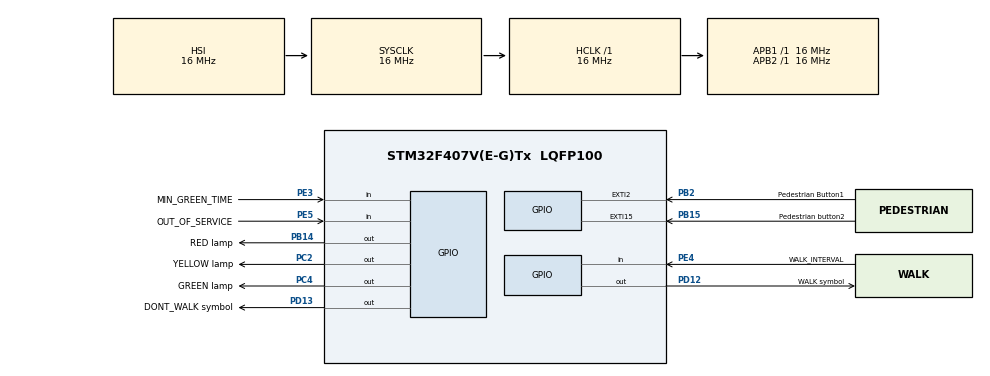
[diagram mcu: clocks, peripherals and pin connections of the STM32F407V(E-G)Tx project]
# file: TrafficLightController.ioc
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Mcu.Family=STM32F4
Mcu.Name=STM32F407V(E-G)Tx
Mcu.Package=LQFP100
NVIC.PriorityGroup=NVIC_PRIORITYGROUP_4
PA13.Mode=Serial_Wire
PA13.Signal=SYS_JTMS-SWDIO
PA14.Mode=Serial_Wire
PA14.Signal=SYS_JTCK-SWCLK
PB14.GPIO_Label=RED lamp
PB14.Signal=GPIO_Output
PB15.GPIO_Label=Pedestrian button2
PB15.GPIO_ModeDefaultEXTI=GPIO_MODE_IT_FALLING
PB15.Signal=GPXTI15
PB2.GPIO_Label=Pedestrian Button1
PB2.GPIO_ModeDefaultEXTI=GPIO_MODE_IT_FALLING
PB2.Signal=GPXTI2
PC2.GPIO_Label=YELLOW lamp
PC2.Signal=GPIO_Output
PC4.GPIO_Label=GREEN lamp
PC4.Signal=GPIO_Output
PD12.GPIO_Label=WALK symbol
PD12.Signal=GPIO_Output
PD13.GPIO_Label=DONT_WALK symbol
PD13.Signal=GPIO_Output
PE3.GPIO_Label=MIN_GREEN_TIME
PE3.Signal=GPIO_Input
PE4.GPIO_Label=WALK_INTERVAL
PE4.Signal=GPIO_Input
PE5.GPIO_Label=OUT_OF_SERVICE
PE5.Signal=GPIO_Input
ProjectManager.HeapSize=0x200
ProjectManager.StackSize=0x400
ProjectManager.TargetToolchain=MDK-ARM V5
RCC.AHBFreq_Value=16000000
RCC.APB1Freq_Value=16000000
RCC.APB2Freq_Value=16000000
RCC.CortexFreq_Value=16000000
RCC.HSE_VALUE=25000000
RCC.HSI_VALUE=16000000
RCC.LSE_VALUE=32768
RCC.SYSCLKFreq_VALUE=16000000
RCC.VCOOutputFreq_Value=192000000
board=custom

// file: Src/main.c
/* USER CODE BEGIN Header */
/**
  ******************************************************************************
  * @file           : main.c
  * @brief          : Main program body
  ******************************************************************************
  * @attention
  *
  * <h2><center>&copy; Copyright (c) 2019 STMicroelectronics.
  * All rights reserved.</center></h2>
  *
  * This software component is licensed by ST under BSD 3-Clause license,
  * the "License"; You may not use this file except in compliance with the
  * License. You may obtain a copy of the License at:
  *                        opensource.org/licenses/BSD-3-Clause
  *
  ******************************************************************************
  */
/* USER CODE END Header */

#include "main.h"

/* USER CODE BEGIN Includes */
#include <stdio.h>
#include "bsp.h"
#include "timer.h"
#include "ctrler.h"
/* USER CODE END Includes */

void SystemClock_Config(void);
static void MX_GPIO_Init(void);

/* USER CODE BEGIN 0 */
int fputc(int ch, FILE *f)
{
	return ITM_SendChar(ch);
}

Event_t Event_Detect()
{
	Event_t evt = NO_EVT ;
							if (Timeout_Status){
									evt = TIMEOUT ;
									Timeout_Status = 0 ;
							}

							if (Button_Status) {
									evt = BUTTON ;
									Button_Status = 0 ;
							}

							if (MODE_READ()) {
									evt = MODE_CHANGE ;
							}
	return evt ;
}
/* USER CODE END 0 */

int main(void)
{

  /* MCU Configuration--------------------------------------------------------*/

  /* Reset of all peripherals, Initializes the Flash interface and the Systick. */
  HAL_Init();

  /* Configure the system clock */
  SystemClock_Config();

  /* Initialize all configured peripherals */
  MX_GPIO_Init();

  /* Infinite loop */
  while (1)
  {

    /* USER CODE BEGIN 3 */

		Event_t evt = Event_Detect(); //detect event
		uint32_t timeout_value = Ctrler_Exec(evt) ; //Execute state machine, return timeout
		Timeout_Config(timeout_value) ; //set timeout value in timer
		MIN_GREEN_TIME = GREEN_TIME_READ() ? 600:1200 ;
		WALK_INTERVAL = WALK_READ() ? 100:200 ;
		Delay(1);
  }
  /* USER CODE END 3 */
}

void SystemClock_Config(void)
{
  RCC_OscInitTypeDef RCC_OscInitStruct = {0};
  RCC_ClkInitTypeDef RCC_ClkInitStruct = {0};

  /** Configure the main internal regulator output voltage
  */
  __HAL_RCC_PWR_CLK_ENABLE();
  __HAL_PWR_VOLTAGESCALING_CONFIG(PWR_REGULATOR_VOLTAGE_SCALE1);
  /** Initializes the CPU, AHB and APB busses clocks
  */
  RCC_OscInitStruct.OscillatorType = RCC_OSCILLATORTYPE_HSI;
  RCC_OscInitStruct.HSIState = RCC_HSI_ON;
  RCC_OscInitStruct.HSICalibrationValue = RCC_HSICALIBRATION_DEFAULT;
  RCC_OscInitStruct.PLL.PLLState = RCC_PLL_NONE;
  if (HAL_RCC_OscConfig(&RCC_OscInitStruct) != HAL_OK)
  {
    Error_Handler();
  }
  /** Initializes the CPU, AHB and APB busses clocks
  */
  RCC_ClkInitStruct.ClockType = RCC_CLOCKTYPE_HCLK|RCC_CLOCKTYPE_SYSCLK
                              |RCC_CLOCKTYPE_PCLK1|RCC_CLOCKTYPE_PCLK2;
  RCC_ClkInitStruct.SYSCLKSource = RCC_SYSCLKSOURCE_HSI;
  RCC_ClkInitStruct.AHBCLKDivider = RCC_SYSCLK_DIV1;
  RCC_ClkInitStruct.APB1CLKDivider = RCC_HCLK_DIV1;
  RCC_ClkInitStruct.APB2CLKDivider = RCC_HCLK_DIV1;

  if (HAL_RCC_ClockConfig(&RCC_ClkInitStruct, FLASH_LATENCY_0) != HAL_OK)
  {
    Error_Handler();
  }
}

static void MX_GPIO_Init(void)
{
  GPIO_InitTypeDef GPIO_InitStruct = {0};

  /* GPIO Ports Clock Enable */
  __HAL_RCC_GPIOE_CLK_ENABLE();
  __HAL_RCC_GPIOC_CLK_ENABLE();
  __HAL_RCC_GPIOB_CLK_ENABLE();
  __HAL_RCC_GPIOD_CLK_ENABLE();
  __HAL_RCC_GPIOA_CLK_ENABLE();

  /*Configure GPIO pin Output Level */
  HAL_GPIO_WritePin(GPIOC, YELLOW_LAMP_Pin|GREEN_LAMP_Pin, GPIO_PIN_RESET);

  /*Configure GPIO pin Output Level */
  HAL_GPIO_WritePin(RED_LAMP_GPIO_Port, RED_LAMP_Pin, GPIO_PIN_RESET);

  /*Configure GPIO pin Output Level */
  HAL_GPIO_WritePin(GPIOD, WALK_Pin|DONT_WALK_Pin, GPIO_PIN_RESET);

  /*Configure GPIO pins : MIN_GREEN_TIME_Pin WALK_INTERVAL_Pin OUT_OF_SERVICE_Pin */
  GPIO_InitStruct.Pin = MIN_GREEN_SW_Pin|WALK_INTERVAL_SW_Pin|MODE_SW_Pin;
  GPIO_InitStruct.Mode = GPIO_MODE_INPUT;
  GPIO_InitStruct.Pull = GPIO_NOPULL;
  HAL_GPIO_Init(GPIOE, &GPIO_InitStruct);

  /*Configure GPIO pins : YELLOW_lamp_Pin GREEN_lamp_Pin */
  GPIO_InitStruct.Pin = YELLOW_LAMP_Pin|GREEN_LAMP_Pin;
  GPIO_InitStruct.Mode = GPIO_MODE_OUTPUT_PP;
  GPIO_InitStruct.Pull = GPIO_NOPULL;
  GPIO_InitStruct.Speed = GPIO_SPEED_FREQ_LOW;
  HAL_GPIO_Init(GPIOC, &GPIO_InitStruct);

  /*Configure GPIO pins : Pedestrian_Button1_Pin Pedestrian_button2_Pin */
  GPIO_InitStruct.Pin = BUTTON1_Pin;
  GPIO_InitStruct.Mode = GPIO_MODE_IT_FALLING;
  GPIO_InitStruct.Pull = GPIO_NOPULL;
  HAL_GPIO_Init(GPIOB, &GPIO_InitStruct);

  /*Configure GPIO pin : RED_lamp_Pin */
  GPIO_InitStruct.Pin = RED_LAMP_Pin;
  GPIO_InitStruct.Mode = GPIO_MODE_OUTPUT_PP;
  GPIO_InitStruct.Pull = GPIO_NOPULL;
  GPIO_InitStruct.Speed = GPIO_SPEED_FREQ_LOW;
  HAL_GPIO_Init(RED_LAMP_GPIO_Port, &GPIO_InitStruct);

  /*Configure GPIO pins : WALK_symbol_Pin DONT_WALK_symbol_Pin */
  GPIO_InitStruct.Pin = WALK_Pin|DONT_WALK_Pin;
  GPIO_InitStruct.Mode = GPIO_MODE_OUTPUT_PP;
  GPIO_InitStruct.Pull = GPIO_NOPULL;
  GPIO_InitStruct.Speed = GPIO_SPEED_FREQ_LOW;
  HAL_GPIO_Init(GPIOD, &GPIO_InitStruct);

}

void Error_Handler(void)
{
}

/************************ (C) COPYRIGHT STMicroelectronics *****END OF FILE****/
